VERSION 5.7 ;
  NOWIREEXTENSIONATPIN ON ;
  DIVIDERCHAR "/" ;
  BUSBITCHARS "[]" ;
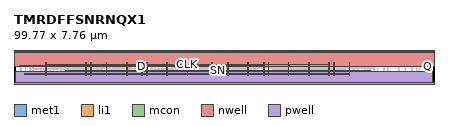
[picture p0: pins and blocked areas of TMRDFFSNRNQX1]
MACRO TMRDFFSNRNQX1
  CLASS CORE ;
  FOREIGN TMRDFFSNRNQX1 ;
  ORIGIN 0.000 0.000 ;
  SIZE 99.770 BY 7.760 ;
  SYMMETRY X Y ;
  SITE unitrh ;
  PIN Q
    DIRECTION OUTPUT ;
    USE SIGNAL ;
    ANTENNADIFFAREA 0.771900 ;
    PORT
      LAYER met1 ;
        RECT 98.425 4.335 98.655 4.365 ;
        RECT 98.395 4.165 98.805 4.335 ;
        RECT 98.425 4.135 98.655 4.165 ;
    END
  END Q
  PIN D
    DIRECTION INPUT ;
    USE SIGNAL ;
    ANTENNAGATEAREA 3.099750 ;
    PORT
      LAYER met1 ;
        RECT 1.485 4.335 1.715 4.365 ;
        RECT 30.345 4.335 30.575 4.365 ;
        RECT 59.205 4.335 59.435 4.365 ;
        RECT 1.335 4.165 59.465 4.335 ;
        RECT 1.485 4.135 1.715 4.165 ;
        RECT 30.345 4.135 30.575 4.165 ;
        RECT 59.205 4.135 59.435 4.165 ;
    END
    PORT
      LAYER li1 ;
        RECT 30.375 2.095 30.545 5.045 ;
      LAYER mcon ;
        RECT 30.375 4.165 30.545 4.335 ;
    END
    PORT
      LAYER li1 ;
        RECT 59.235 2.095 59.405 5.045 ;
      LAYER mcon ;
        RECT 59.235 4.165 59.405 4.335 ;
    END
  END D
  PIN CLK
    DIRECTION INPUT ;
    USE SIGNAL ;
    ANTENNAGATEAREA 6.089100 ;
    PORT
      LAYER met1 ;
        RECT 7.405 4.705 7.635 4.735 ;
        RECT 17.025 4.705 17.255 4.735 ;
        RECT 36.265 4.705 36.495 4.735 ;
        RECT 45.885 4.705 46.115 4.735 ;
        RECT 65.125 4.705 65.355 4.735 ;
        RECT 74.745 4.705 74.975 4.735 ;
        RECT 7.375 4.535 75.005 4.705 ;
        RECT 7.405 4.505 7.635 4.535 ;
        RECT 17.025 4.505 17.255 4.535 ;
        RECT 36.265 4.505 36.495 4.535 ;
        RECT 45.885 4.505 46.115 4.535 ;
        RECT 65.125 4.505 65.355 4.535 ;
        RECT 74.745 4.505 74.975 4.535 ;
    END
    PORT
      LAYER li1 ;
        RECT 36.295 2.095 36.465 5.045 ;
      LAYER mcon ;
        RECT 36.295 4.535 36.465 4.705 ;
    END
    PORT
      LAYER li1 ;
        RECT 17.055 2.095 17.225 5.045 ;
      LAYER mcon ;
        RECT 17.055 4.535 17.225 4.705 ;
    END
    PORT
      LAYER li1 ;
        RECT 7.435 2.095 7.605 5.045 ;
      LAYER mcon ;
        RECT 7.435 4.535 7.605 4.705 ;
    END
    PORT
      LAYER li1 ;
        RECT 65.155 2.095 65.325 5.045 ;
      LAYER mcon ;
        RECT 65.155 4.535 65.325 4.705 ;
    END
    PORT
      LAYER li1 ;
        RECT 74.775 2.095 74.945 5.045 ;
      LAYER mcon ;
        RECT 74.775 4.535 74.945 4.705 ;
    END
  END CLK
  PIN SN
    DIRECTION INPUT ;
    USE SIGNAL ;
    ANTENNAGATEAREA 6.089100 ;
    PORT
      LAYER met1 ;
        RECT 12.215 3.225 12.445 3.255 ;
        RECT 26.645 3.225 26.875 3.255 ;
        RECT 41.075 3.225 41.305 3.255 ;
        RECT 55.505 3.225 55.735 3.255 ;
        RECT 69.935 3.225 70.165 3.255 ;
        RECT 84.365 3.225 84.595 3.255 ;
        RECT 12.185 3.055 84.625 3.225 ;
        RECT 12.215 3.025 12.445 3.055 ;
        RECT 26.645 3.025 26.875 3.055 ;
        RECT 41.075 3.025 41.305 3.055 ;
        RECT 55.505 3.025 55.735 3.055 ;
        RECT 69.935 3.025 70.165 3.055 ;
        RECT 84.365 3.025 84.595 3.055 ;
    END
    PORT
      LAYER li1 ;
        RECT 26.675 2.095 26.845 5.045 ;
      LAYER mcon ;
        RECT 26.675 3.055 26.845 3.225 ;
    END
    PORT
      LAYER li1 ;
        RECT 41.105 2.095 41.275 5.045 ;
      LAYER mcon ;
        RECT 41.105 3.055 41.275 3.225 ;
    END
    PORT
      LAYER li1 ;
        RECT 55.535 2.095 55.705 5.045 ;
      LAYER mcon ;
        RECT 55.535 3.055 55.705 3.225 ;
    END
    PORT
      LAYER li1 ;
        RECT 69.965 2.095 70.135 5.045 ;
      LAYER mcon ;
        RECT 69.965 3.055 70.135 3.225 ;
    END
  END SN
  PIN RN
    DIRECTION INPUT ;
    USE SIGNAL ;
    ANTENNAGATEAREA 9.170850 ;
    PORT
      LAYER met1 ;
        RECT 2.595 2.485 2.825 2.515 ;
        RECT 18.135 2.485 18.365 2.515 ;
        RECT 21.835 2.485 22.065 2.515 ;
        RECT 31.455 2.485 31.685 2.515 ;
        RECT 46.995 2.485 47.225 2.515 ;
        RECT 50.695 2.485 50.925 2.515 ;
        RECT 60.315 2.485 60.545 2.515 ;
        RECT 75.855 2.485 76.085 2.515 ;
        RECT 79.555 2.485 79.785 2.515 ;
        RECT 2.565 2.315 79.815 2.485 ;
        RECT 2.595 2.285 2.825 2.315 ;
        RECT 18.135 2.285 18.365 2.315 ;
        RECT 21.835 2.285 22.065 2.315 ;
        RECT 31.455 2.285 31.685 2.315 ;
        RECT 46.995 2.285 47.225 2.315 ;
        RECT 50.695 2.285 50.925 2.315 ;
        RECT 60.315 2.285 60.545 2.315 ;
        RECT 75.855 2.285 76.085 2.315 ;
        RECT 79.555 2.285 79.785 2.315 ;
    END
    PORT
      LAYER li1 ;
        RECT 18.165 2.095 18.335 5.045 ;
      LAYER mcon ;
        RECT 18.165 2.315 18.335 2.485 ;
    END
    PORT
      LAYER li1 ;
        RECT 21.865 2.095 22.035 5.045 ;
      LAYER mcon ;
        RECT 21.865 2.315 22.035 2.485 ;
    END
    PORT
      LAYER li1 ;
        RECT 31.485 2.095 31.655 5.045 ;
      LAYER mcon ;
        RECT 31.485 2.315 31.655 2.485 ;
    END
    PORT
      LAYER li1 ;
        RECT 47.025 2.095 47.195 5.045 ;
      LAYER mcon ;
        RECT 47.025 2.315 47.195 2.485 ;
    END
    PORT
      LAYER li1 ;
        RECT 50.725 2.095 50.895 5.045 ;
      LAYER mcon ;
        RECT 50.725 2.315 50.895 2.485 ;
    END
    PORT
      LAYER li1 ;
        RECT 60.345 2.095 60.515 5.045 ;
      LAYER mcon ;
        RECT 60.345 2.315 60.515 2.485 ;
    END
    PORT
      LAYER li1 ;
        RECT 75.885 2.095 76.055 5.045 ;
      LAYER mcon ;
        RECT 75.885 2.315 76.055 2.485 ;
    END
    PORT
      LAYER li1 ;
        RECT 79.585 2.095 79.755 5.045 ;
      LAYER mcon ;
        RECT 79.585 2.315 79.755 2.485 ;
    END
  END RN
  PIN VDD
    DIRECTION INOUT ;
    USE POWER ;
    SHAPE ABUTMENT ;
    PORT
      LAYER nwell ;
        RECT 0.000 4.110 99.770 7.940 ;
      LAYER met1 ;
        RECT 0.000 7.410 99.770 7.760 ;
    END
  END VDD
  PIN GND
    DIRECTION INOUT ;
    USE GROUND ;
    SHAPE ABUTMENT ;
    PORT
      LAYER pwell ;
        RECT 0.320 0.000 99.450 2.900 ;
      LAYER met1 ;
        RECT 0.000 0.000 99.770 0.350 ;
    END
  END GND
  OBS
      LAYER li1 ;
        RECT 0.000 7.410 99.770 7.760 ;
        RECT 0.320 4.290 0.660 7.410 ;
        RECT 1.495 5.395 1.665 7.410 ;
        RECT 1.935 5.420 2.105 7.200 ;
        RECT 2.375 5.735 2.545 7.410 ;
        RECT 2.815 5.420 2.985 7.200 ;
        RECT 3.255 5.735 3.425 7.410 ;
        RECT 3.695 5.420 3.865 7.200 ;
        RECT 4.135 5.735 4.305 7.410 ;
        RECT 1.935 5.250 4.645 5.420 ;
        RECT 0.320 0.350 0.660 2.900 ;
        RECT 1.515 2.095 1.685 5.045 ;
        RECT 2.625 2.095 2.795 5.045 ;
        RECT 3.735 2.095 3.905 5.045 ;
        RECT 0.995 1.855 1.165 1.935 ;
        RECT 1.965 1.855 2.135 1.935 ;
        RECT 2.935 1.855 3.105 1.935 ;
        RECT 0.995 1.685 3.105 1.855 ;
        RECT 0.995 0.555 1.165 1.685 ;
        RECT 1.480 0.350 1.650 1.310 ;
        RECT 1.965 0.805 2.135 1.685 ;
        RECT 2.935 1.605 3.105 1.685 ;
        RECT 2.455 1.260 2.625 1.340 ;
        RECT 3.505 1.260 3.675 1.935 ;
        RECT 4.475 1.930 4.645 5.250 ;
        RECT 5.130 4.290 5.470 7.410 ;
        RECT 6.305 5.395 6.475 7.410 ;
        RECT 6.745 5.420 6.915 7.200 ;
        RECT 7.185 5.735 7.355 7.410 ;
        RECT 7.625 5.420 7.795 7.200 ;
        RECT 8.065 5.735 8.235 7.410 ;
        RECT 8.505 5.420 8.675 7.200 ;
        RECT 8.945 5.735 9.115 7.410 ;
        RECT 6.745 5.250 9.455 5.420 ;
        RECT 2.455 1.090 3.675 1.260 ;
        RECT 2.455 1.010 2.625 1.090 ;
        RECT 2.935 0.805 3.105 0.885 ;
        RECT 1.965 0.635 3.105 0.805 ;
        RECT 1.965 0.555 2.135 0.635 ;
        RECT 2.935 0.555 3.105 0.635 ;
        RECT 3.505 0.805 3.675 1.090 ;
        RECT 3.990 1.760 4.645 1.930 ;
        RECT 3.990 1.025 4.160 1.760 ;
        RECT 4.475 0.805 4.645 1.575 ;
        RECT 3.505 0.635 4.645 0.805 ;
        RECT 3.505 0.555 3.675 0.635 ;
        RECT 4.475 0.555 4.645 0.635 ;
        RECT 5.130 0.350 5.470 2.900 ;
        RECT 6.325 2.095 6.495 5.045 ;
        RECT 8.545 2.095 8.715 5.045 ;
        RECT 5.805 1.855 5.975 1.935 ;
        RECT 6.775 1.855 6.945 1.935 ;
        RECT 7.745 1.855 7.915 1.935 ;
        RECT 5.805 1.685 7.915 1.855 ;
        RECT 5.805 0.555 5.975 1.685 ;
        RECT 6.290 0.350 6.460 1.310 ;
        RECT 6.775 0.805 6.945 1.685 ;
        RECT 7.745 1.605 7.915 1.685 ;
        RECT 7.265 1.260 7.435 1.340 ;
        RECT 8.315 1.260 8.485 1.935 ;
        RECT 9.285 1.930 9.455 5.250 ;
        RECT 9.940 4.290 10.280 7.410 ;
        RECT 11.115 5.395 11.285 7.410 ;
        RECT 11.555 5.420 11.725 7.200 ;
        RECT 11.995 5.735 12.165 7.410 ;
        RECT 12.435 5.420 12.605 7.200 ;
        RECT 12.875 5.735 13.045 7.410 ;
        RECT 13.315 5.420 13.485 7.200 ;
        RECT 13.755 5.735 13.925 7.410 ;
        RECT 11.555 5.250 14.265 5.420 ;
        RECT 7.265 1.090 8.485 1.260 ;
        RECT 7.265 1.010 7.435 1.090 ;
        RECT 7.745 0.805 7.915 0.885 ;
        RECT 6.775 0.635 7.915 0.805 ;
        RECT 6.775 0.555 6.945 0.635 ;
        RECT 7.745 0.555 7.915 0.635 ;
        RECT 8.315 0.805 8.485 1.090 ;
        RECT 8.800 1.760 9.455 1.930 ;
        RECT 8.800 1.025 8.970 1.760 ;
        RECT 9.285 0.805 9.455 1.575 ;
        RECT 8.315 0.635 9.455 0.805 ;
        RECT 8.315 0.555 8.485 0.635 ;
        RECT 9.285 0.555 9.455 0.635 ;
        RECT 9.940 0.350 10.280 2.900 ;
        RECT 11.135 2.095 11.305 5.045 ;
        RECT 12.245 2.095 12.415 5.045 ;
        RECT 13.355 2.095 13.525 5.045 ;
        RECT 10.615 1.855 10.785 1.935 ;
        RECT 11.585 1.855 11.755 1.935 ;
        RECT 12.555 1.855 12.725 1.935 ;
        RECT 10.615 1.685 12.725 1.855 ;
        RECT 10.615 0.555 10.785 1.685 ;
        RECT 11.100 0.350 11.270 1.310 ;
        RECT 11.585 0.805 11.755 1.685 ;
        RECT 12.555 1.605 12.725 1.685 ;
        RECT 12.075 1.260 12.245 1.340 ;
        RECT 13.125 1.260 13.295 1.935 ;
        RECT 14.095 1.930 14.265 5.250 ;
        RECT 14.750 4.290 15.090 7.410 ;
        RECT 15.925 5.395 16.095 7.410 ;
        RECT 16.365 5.420 16.535 7.200 ;
        RECT 16.805 5.735 16.975 7.410 ;
        RECT 17.245 5.420 17.415 7.200 ;
        RECT 17.685 5.735 17.855 7.410 ;
        RECT 18.125 5.420 18.295 7.200 ;
        RECT 18.565 5.735 18.735 7.410 ;
        RECT 16.365 5.250 19.075 5.420 ;
        RECT 12.075 1.090 13.295 1.260 ;
        RECT 12.075 1.010 12.245 1.090 ;
        RECT 12.555 0.805 12.725 0.885 ;
        RECT 11.585 0.635 12.725 0.805 ;
        RECT 11.585 0.555 11.755 0.635 ;
        RECT 12.555 0.555 12.725 0.635 ;
        RECT 13.125 0.805 13.295 1.090 ;
        RECT 13.610 1.760 14.265 1.930 ;
        RECT 13.610 1.025 13.780 1.760 ;
        RECT 14.095 0.805 14.265 1.575 ;
        RECT 13.125 0.635 14.265 0.805 ;
        RECT 13.125 0.555 13.295 0.635 ;
        RECT 14.095 0.555 14.265 0.635 ;
        RECT 14.750 0.350 15.090 2.900 ;
        RECT 15.945 2.095 16.115 5.045 ;
        RECT 15.425 1.855 15.595 1.935 ;
        RECT 16.395 1.855 16.565 1.935 ;
        RECT 17.365 1.855 17.535 1.935 ;
        RECT 15.425 1.685 17.535 1.855 ;
        RECT 15.425 0.555 15.595 1.685 ;
        RECT 15.910 0.350 16.080 1.310 ;
        RECT 16.395 0.805 16.565 1.685 ;
        RECT 17.365 1.605 17.535 1.685 ;
        RECT 16.885 1.260 17.055 1.340 ;
        RECT 17.935 1.260 18.105 1.935 ;
        RECT 18.905 1.930 19.075 5.250 ;
        RECT 19.560 4.290 19.900 7.410 ;
        RECT 20.735 5.395 20.905 7.410 ;
        RECT 21.175 5.420 21.345 7.200 ;
        RECT 21.615 5.735 21.785 7.410 ;
        RECT 22.055 5.420 22.225 7.200 ;
        RECT 22.495 5.735 22.665 7.410 ;
        RECT 22.935 5.420 23.105 7.200 ;
        RECT 23.375 5.735 23.545 7.410 ;
        RECT 21.175 5.250 23.885 5.420 ;
        RECT 16.885 1.090 18.105 1.260 ;
        RECT 16.885 1.010 17.055 1.090 ;
        RECT 17.365 0.805 17.535 0.885 ;
        RECT 16.395 0.635 17.535 0.805 ;
        RECT 16.395 0.555 16.565 0.635 ;
        RECT 17.365 0.555 17.535 0.635 ;
        RECT 17.935 0.805 18.105 1.090 ;
        RECT 18.420 1.760 19.075 1.930 ;
        RECT 18.420 1.025 18.590 1.760 ;
        RECT 18.905 0.805 19.075 1.575 ;
        RECT 17.935 0.635 19.075 0.805 ;
        RECT 17.935 0.555 18.105 0.635 ;
        RECT 18.905 0.555 19.075 0.635 ;
        RECT 19.560 0.350 19.900 2.900 ;
        RECT 20.755 2.095 20.925 5.045 ;
        RECT 22.975 2.095 23.145 5.045 ;
        RECT 20.235 1.855 20.405 1.935 ;
        RECT 21.205 1.855 21.375 1.935 ;
        RECT 22.175 1.855 22.345 1.935 ;
        RECT 20.235 1.685 22.345 1.855 ;
        RECT 20.235 0.555 20.405 1.685 ;
        RECT 20.720 0.350 20.890 1.310 ;
        RECT 21.205 0.805 21.375 1.685 ;
        RECT 22.175 1.605 22.345 1.685 ;
        RECT 21.695 1.260 21.865 1.340 ;
        RECT 22.745 1.260 22.915 1.935 ;
        RECT 23.715 1.930 23.885 5.250 ;
        RECT 24.370 4.290 24.710 7.410 ;
        RECT 25.545 5.395 25.715 7.410 ;
        RECT 25.985 5.420 26.155 7.200 ;
        RECT 26.425 5.735 26.595 7.410 ;
        RECT 26.865 5.420 27.035 7.200 ;
        RECT 27.305 5.735 27.475 7.410 ;
        RECT 27.745 5.420 27.915 7.200 ;
        RECT 28.185 5.735 28.355 7.410 ;
        RECT 25.985 5.250 28.695 5.420 ;
        RECT 21.695 1.090 22.915 1.260 ;
        RECT 21.695 1.010 21.865 1.090 ;
        RECT 22.175 0.805 22.345 0.885 ;
        RECT 21.205 0.635 22.345 0.805 ;
        RECT 21.205 0.555 21.375 0.635 ;
        RECT 22.175 0.555 22.345 0.635 ;
        RECT 22.745 0.805 22.915 1.090 ;
        RECT 23.230 1.760 23.885 1.930 ;
        RECT 23.230 1.025 23.400 1.760 ;
        RECT 23.715 0.805 23.885 1.575 ;
        RECT 22.745 0.635 23.885 0.805 ;
        RECT 22.745 0.555 22.915 0.635 ;
        RECT 23.715 0.555 23.885 0.635 ;
        RECT 24.370 0.350 24.710 2.900 ;
        RECT 25.565 2.095 25.735 5.045 ;
        RECT 27.785 2.095 27.955 5.045 ;
        RECT 25.045 1.855 25.215 1.935 ;
        RECT 26.015 1.855 26.185 1.935 ;
        RECT 26.985 1.855 27.155 1.935 ;
        RECT 25.045 1.685 27.155 1.855 ;
        RECT 25.045 0.555 25.215 1.685 ;
        RECT 25.530 0.350 25.700 1.310 ;
        RECT 26.015 0.805 26.185 1.685 ;
        RECT 26.985 1.605 27.155 1.685 ;
        RECT 26.505 1.260 26.675 1.340 ;
        RECT 27.555 1.260 27.725 1.935 ;
        RECT 28.525 1.930 28.695 5.250 ;
        RECT 29.180 4.290 29.520 7.410 ;
        RECT 30.355 5.395 30.525 7.410 ;
        RECT 30.795 5.420 30.965 7.200 ;
        RECT 31.235 5.735 31.405 7.410 ;
        RECT 31.675 5.420 31.845 7.200 ;
        RECT 32.115 5.735 32.285 7.410 ;
        RECT 32.555 5.420 32.725 7.200 ;
        RECT 32.995 5.735 33.165 7.410 ;
        RECT 30.795 5.250 33.505 5.420 ;
        RECT 26.505 1.090 27.725 1.260 ;
        RECT 26.505 1.010 26.675 1.090 ;
        RECT 26.985 0.805 27.155 0.885 ;
        RECT 26.015 0.635 27.155 0.805 ;
        RECT 26.015 0.555 26.185 0.635 ;
        RECT 26.985 0.555 27.155 0.635 ;
        RECT 27.555 0.805 27.725 1.090 ;
        RECT 28.040 1.760 28.695 1.930 ;
        RECT 28.040 1.025 28.210 1.760 ;
        RECT 28.525 0.805 28.695 1.575 ;
        RECT 27.555 0.635 28.695 0.805 ;
        RECT 27.555 0.555 27.725 0.635 ;
        RECT 28.525 0.555 28.695 0.635 ;
        RECT 29.180 0.350 29.520 2.900 ;
        RECT 32.595 2.095 32.765 5.045 ;
        RECT 29.855 1.855 30.025 1.935 ;
        RECT 30.825 1.855 30.995 1.935 ;
        RECT 31.795 1.855 31.965 1.935 ;
        RECT 29.855 1.685 31.965 1.855 ;
        RECT 29.855 0.555 30.025 1.685 ;
        RECT 30.340 0.350 30.510 1.310 ;
        RECT 30.825 0.805 30.995 1.685 ;
        RECT 31.795 1.605 31.965 1.685 ;
        RECT 31.315 1.260 31.485 1.340 ;
        RECT 32.365 1.260 32.535 1.935 ;
        RECT 33.335 1.930 33.505 5.250 ;
        RECT 33.990 4.290 34.330 7.410 ;
        RECT 35.165 5.395 35.335 7.410 ;
        RECT 35.605 5.420 35.775 7.200 ;
        RECT 36.045 5.735 36.215 7.410 ;
        RECT 36.485 5.420 36.655 7.200 ;
        RECT 36.925 5.735 37.095 7.410 ;
        RECT 37.365 5.420 37.535 7.200 ;
        RECT 37.805 5.735 37.975 7.410 ;
        RECT 35.605 5.250 38.315 5.420 ;
        RECT 31.315 1.090 32.535 1.260 ;
        RECT 31.315 1.010 31.485 1.090 ;
        RECT 31.795 0.805 31.965 0.885 ;
        RECT 30.825 0.635 31.965 0.805 ;
        RECT 30.825 0.555 30.995 0.635 ;
        RECT 31.795 0.555 31.965 0.635 ;
        RECT 32.365 0.805 32.535 1.090 ;
        RECT 32.850 1.760 33.505 1.930 ;
        RECT 32.850 1.025 33.020 1.760 ;
        RECT 33.335 0.805 33.505 1.575 ;
        RECT 32.365 0.635 33.505 0.805 ;
        RECT 32.365 0.555 32.535 0.635 ;
        RECT 33.335 0.555 33.505 0.635 ;
        RECT 33.990 0.350 34.330 2.900 ;
        RECT 35.185 2.095 35.355 5.045 ;
        RECT 37.405 2.095 37.575 5.045 ;
        RECT 34.665 1.855 34.835 1.935 ;
        RECT 35.635 1.855 35.805 1.935 ;
        RECT 36.605 1.855 36.775 1.935 ;
        RECT 34.665 1.685 36.775 1.855 ;
        RECT 34.665 0.555 34.835 1.685 ;
        RECT 35.150 0.350 35.320 1.310 ;
        RECT 35.635 0.805 35.805 1.685 ;
        RECT 36.605 1.605 36.775 1.685 ;
        RECT 36.125 1.260 36.295 1.340 ;
        RECT 37.175 1.260 37.345 1.935 ;
        RECT 38.145 1.930 38.315 5.250 ;
        RECT 38.800 4.290 39.140 7.410 ;
        RECT 39.975 5.395 40.145 7.410 ;
        RECT 40.415 5.420 40.585 7.200 ;
        RECT 40.855 5.735 41.025 7.410 ;
        RECT 41.295 5.420 41.465 7.200 ;
        RECT 41.735 5.735 41.905 7.410 ;
        RECT 42.175 5.420 42.345 7.200 ;
        RECT 42.615 5.735 42.785 7.410 ;
        RECT 40.415 5.250 43.125 5.420 ;
        RECT 36.125 1.090 37.345 1.260 ;
        RECT 36.125 1.010 36.295 1.090 ;
        RECT 36.605 0.805 36.775 0.885 ;
        RECT 35.635 0.635 36.775 0.805 ;
        RECT 35.635 0.555 35.805 0.635 ;
        RECT 36.605 0.555 36.775 0.635 ;
        RECT 37.175 0.805 37.345 1.090 ;
        RECT 37.660 1.760 38.315 1.930 ;
        RECT 37.660 1.025 37.830 1.760 ;
        RECT 38.145 0.805 38.315 1.575 ;
        RECT 37.175 0.635 38.315 0.805 ;
        RECT 37.175 0.555 37.345 0.635 ;
        RECT 38.145 0.555 38.315 0.635 ;
        RECT 38.800 0.350 39.140 2.900 ;
        RECT 39.995 2.095 40.165 5.045 ;
        RECT 42.215 2.095 42.385 5.045 ;
        RECT 39.475 1.855 39.645 1.935 ;
        RECT 40.445 1.855 40.615 1.935 ;
        RECT 41.415 1.855 41.585 1.935 ;
        RECT 39.475 1.685 41.585 1.855 ;
        RECT 39.475 0.555 39.645 1.685 ;
        RECT 39.960 0.350 40.130 1.310 ;
        RECT 40.445 0.805 40.615 1.685 ;
        RECT 41.415 1.605 41.585 1.685 ;
        RECT 40.935 1.260 41.105 1.340 ;
        RECT 41.985 1.260 42.155 1.935 ;
        RECT 42.955 1.930 43.125 5.250 ;
        RECT 43.610 4.290 43.950 7.410 ;
        RECT 44.785 5.395 44.955 7.410 ;
        RECT 45.225 5.420 45.395 7.200 ;
        RECT 45.665 5.735 45.835 7.410 ;
        RECT 46.105 5.420 46.275 7.200 ;
        RECT 46.545 5.735 46.715 7.410 ;
        RECT 46.985 5.420 47.155 7.200 ;
        RECT 47.425 5.735 47.595 7.410 ;
        RECT 45.225 5.250 47.935 5.420 ;
        RECT 40.935 1.090 42.155 1.260 ;
        RECT 40.935 1.010 41.105 1.090 ;
        RECT 41.415 0.805 41.585 0.885 ;
        RECT 40.445 0.635 41.585 0.805 ;
        RECT 40.445 0.555 40.615 0.635 ;
        RECT 41.415 0.555 41.585 0.635 ;
        RECT 41.985 0.805 42.155 1.090 ;
        RECT 42.470 1.760 43.125 1.930 ;
        RECT 42.470 1.025 42.640 1.760 ;
        RECT 42.955 0.805 43.125 1.575 ;
        RECT 41.985 0.635 43.125 0.805 ;
        RECT 41.985 0.555 42.155 0.635 ;
        RECT 42.955 0.555 43.125 0.635 ;
        RECT 43.610 0.350 43.950 2.900 ;
        RECT 44.805 2.095 44.975 5.045 ;
        RECT 45.915 2.095 46.085 5.045 ;
        RECT 44.285 1.855 44.455 1.935 ;
        RECT 45.255 1.855 45.425 1.935 ;
        RECT 46.225 1.855 46.395 1.935 ;
        RECT 44.285 1.685 46.395 1.855 ;
        RECT 44.285 0.555 44.455 1.685 ;
        RECT 44.770 0.350 44.940 1.310 ;
        RECT 45.255 0.805 45.425 1.685 ;
        RECT 46.225 1.605 46.395 1.685 ;
        RECT 45.745 1.260 45.915 1.340 ;
        RECT 46.795 1.260 46.965 1.935 ;
        RECT 47.765 1.930 47.935 5.250 ;
        RECT 48.420 4.290 48.760 7.410 ;
        RECT 49.595 5.395 49.765 7.410 ;
        RECT 50.035 5.420 50.205 7.200 ;
        RECT 50.475 5.735 50.645 7.410 ;
        RECT 50.915 5.420 51.085 7.200 ;
        RECT 51.355 5.735 51.525 7.410 ;
        RECT 51.795 5.420 51.965 7.200 ;
        RECT 52.235 5.735 52.405 7.410 ;
        RECT 50.035 5.250 52.745 5.420 ;
        RECT 45.745 1.090 46.965 1.260 ;
        RECT 45.745 1.010 45.915 1.090 ;
        RECT 46.225 0.805 46.395 0.885 ;
        RECT 45.255 0.635 46.395 0.805 ;
        RECT 45.255 0.555 45.425 0.635 ;
        RECT 46.225 0.555 46.395 0.635 ;
        RECT 46.795 0.805 46.965 1.090 ;
        RECT 47.280 1.760 47.935 1.930 ;
        RECT 47.280 1.025 47.450 1.760 ;
        RECT 47.765 0.805 47.935 1.575 ;
        RECT 46.795 0.635 47.935 0.805 ;
        RECT 46.795 0.555 46.965 0.635 ;
        RECT 47.765 0.555 47.935 0.635 ;
        RECT 48.420 0.350 48.760 2.900 ;
        RECT 49.615 2.095 49.785 5.045 ;
        RECT 51.835 2.095 52.005 5.045 ;
        RECT 49.095 1.855 49.265 1.935 ;
        RECT 50.065 1.855 50.235 1.935 ;
        RECT 51.035 1.855 51.205 1.935 ;
        RECT 49.095 1.685 51.205 1.855 ;
        RECT 49.095 0.555 49.265 1.685 ;
        RECT 49.580 0.350 49.750 1.310 ;
        RECT 50.065 0.805 50.235 1.685 ;
        RECT 51.035 1.605 51.205 1.685 ;
        RECT 50.555 1.260 50.725 1.340 ;
        RECT 51.605 1.260 51.775 1.935 ;
        RECT 52.575 1.930 52.745 5.250 ;
        RECT 53.230 4.290 53.570 7.410 ;
        RECT 54.405 5.395 54.575 7.410 ;
        RECT 54.845 5.420 55.015 7.200 ;
        RECT 55.285 5.735 55.455 7.410 ;
        RECT 55.725 5.420 55.895 7.200 ;
        RECT 56.165 5.735 56.335 7.410 ;
        RECT 56.605 5.420 56.775 7.200 ;
        RECT 57.045 5.735 57.215 7.410 ;
        RECT 54.845 5.250 57.555 5.420 ;
        RECT 50.555 1.090 51.775 1.260 ;
        RECT 50.555 1.010 50.725 1.090 ;
        RECT 51.035 0.805 51.205 0.885 ;
        RECT 50.065 0.635 51.205 0.805 ;
        RECT 50.065 0.555 50.235 0.635 ;
        RECT 51.035 0.555 51.205 0.635 ;
        RECT 51.605 0.805 51.775 1.090 ;
        RECT 52.090 1.760 52.745 1.930 ;
        RECT 52.090 1.025 52.260 1.760 ;
        RECT 52.575 0.805 52.745 1.575 ;
        RECT 51.605 0.635 52.745 0.805 ;
        RECT 51.605 0.555 51.775 0.635 ;
        RECT 52.575 0.555 52.745 0.635 ;
        RECT 53.230 0.350 53.570 2.900 ;
        RECT 54.425 2.095 54.595 5.045 ;
        RECT 56.645 2.095 56.815 5.045 ;
        RECT 53.905 1.855 54.075 1.935 ;
        RECT 54.875 1.855 55.045 1.935 ;
        RECT 55.845 1.855 56.015 1.935 ;
        RECT 53.905 1.685 56.015 1.855 ;
        RECT 53.905 0.555 54.075 1.685 ;
        RECT 54.390 0.350 54.560 1.310 ;
        RECT 54.875 0.805 55.045 1.685 ;
        RECT 55.845 1.605 56.015 1.685 ;
        RECT 55.365 1.260 55.535 1.340 ;
        RECT 56.415 1.260 56.585 1.935 ;
        RECT 57.385 1.930 57.555 5.250 ;
        RECT 58.040 4.290 58.380 7.410 ;
        RECT 59.215 5.395 59.385 7.410 ;
        RECT 59.655 5.420 59.825 7.200 ;
        RECT 60.095 5.735 60.265 7.410 ;
        RECT 60.535 5.420 60.705 7.200 ;
        RECT 60.975 5.735 61.145 7.410 ;
        RECT 61.415 5.420 61.585 7.200 ;
        RECT 61.855 5.735 62.025 7.410 ;
        RECT 59.655 5.250 62.365 5.420 ;
        RECT 55.365 1.090 56.585 1.260 ;
        RECT 55.365 1.010 55.535 1.090 ;
        RECT 55.845 0.805 56.015 0.885 ;
        RECT 54.875 0.635 56.015 0.805 ;
        RECT 54.875 0.555 55.045 0.635 ;
        RECT 55.845 0.555 56.015 0.635 ;
        RECT 56.415 0.805 56.585 1.090 ;
        RECT 56.900 1.760 57.555 1.930 ;
        RECT 56.900 1.025 57.070 1.760 ;
        RECT 57.385 0.805 57.555 1.575 ;
        RECT 56.415 0.635 57.555 0.805 ;
        RECT 56.415 0.555 56.585 0.635 ;
        RECT 57.385 0.555 57.555 0.635 ;
        RECT 58.040 0.350 58.380 2.900 ;
        RECT 61.455 2.095 61.625 5.045 ;
        RECT 58.715 1.855 58.885 1.935 ;
        RECT 59.685 1.855 59.855 1.935 ;
        RECT 60.655 1.855 60.825 1.935 ;
        RECT 58.715 1.685 60.825 1.855 ;
        RECT 58.715 0.555 58.885 1.685 ;
        RECT 59.200 0.350 59.370 1.310 ;
        RECT 59.685 0.805 59.855 1.685 ;
        RECT 60.655 1.605 60.825 1.685 ;
        RECT 60.175 1.260 60.345 1.340 ;
        RECT 61.225 1.260 61.395 1.935 ;
        RECT 62.195 1.930 62.365 5.250 ;
        RECT 62.850 4.290 63.190 7.410 ;
        RECT 64.025 5.395 64.195 7.410 ;
        RECT 64.465 5.420 64.635 7.200 ;
        RECT 64.905 5.735 65.075 7.410 ;
        RECT 65.345 5.420 65.515 7.200 ;
        RECT 65.785 5.735 65.955 7.410 ;
        RECT 66.225 5.420 66.395 7.200 ;
        RECT 66.665 5.735 66.835 7.410 ;
        RECT 64.465 5.250 67.175 5.420 ;
        RECT 60.175 1.090 61.395 1.260 ;
        RECT 60.175 1.010 60.345 1.090 ;
        RECT 60.655 0.805 60.825 0.885 ;
        RECT 59.685 0.635 60.825 0.805 ;
        RECT 59.685 0.555 59.855 0.635 ;
        RECT 60.655 0.555 60.825 0.635 ;
        RECT 61.225 0.805 61.395 1.090 ;
        RECT 61.710 1.760 62.365 1.930 ;
        RECT 61.710 1.025 61.880 1.760 ;
        RECT 62.195 0.805 62.365 1.575 ;
        RECT 61.225 0.635 62.365 0.805 ;
        RECT 61.225 0.555 61.395 0.635 ;
        RECT 62.195 0.555 62.365 0.635 ;
        RECT 62.850 0.350 63.190 2.900 ;
        RECT 64.045 2.095 64.215 5.045 ;
        RECT 66.265 2.095 66.435 5.045 ;
        RECT 63.525 1.855 63.695 1.935 ;
        RECT 64.495 1.855 64.665 1.935 ;
        RECT 65.465 1.855 65.635 1.935 ;
        RECT 63.525 1.685 65.635 1.855 ;
        RECT 63.525 0.555 63.695 1.685 ;
        RECT 64.010 0.350 64.180 1.310 ;
        RECT 64.495 0.805 64.665 1.685 ;
        RECT 65.465 1.605 65.635 1.685 ;
        RECT 64.985 1.260 65.155 1.340 ;
        RECT 66.035 1.260 66.205 1.935 ;
        RECT 67.005 1.930 67.175 5.250 ;
        RECT 67.660 4.290 68.000 7.410 ;
        RECT 68.835 5.395 69.005 7.410 ;
        RECT 69.275 5.420 69.445 7.200 ;
        RECT 69.715 5.735 69.885 7.410 ;
        RECT 70.155 5.420 70.325 7.200 ;
        RECT 70.595 5.735 70.765 7.410 ;
        RECT 71.035 5.420 71.205 7.200 ;
        RECT 71.475 5.735 71.645 7.410 ;
        RECT 69.275 5.250 71.985 5.420 ;
        RECT 64.985 1.090 66.205 1.260 ;
        RECT 64.985 1.010 65.155 1.090 ;
        RECT 65.465 0.805 65.635 0.885 ;
        RECT 64.495 0.635 65.635 0.805 ;
        RECT 64.495 0.555 64.665 0.635 ;
        RECT 65.465 0.555 65.635 0.635 ;
        RECT 66.035 0.805 66.205 1.090 ;
        RECT 66.520 1.760 67.175 1.930 ;
        RECT 66.520 1.025 66.690 1.760 ;
        RECT 67.005 0.805 67.175 1.575 ;
        RECT 66.035 0.635 67.175 0.805 ;
        RECT 66.035 0.555 66.205 0.635 ;
        RECT 67.005 0.555 67.175 0.635 ;
        RECT 67.660 0.350 68.000 2.900 ;
        RECT 68.855 2.095 69.025 5.045 ;
        RECT 71.075 2.095 71.245 5.045 ;
        RECT 68.335 1.855 68.505 1.935 ;
        RECT 69.305 1.855 69.475 1.935 ;
        RECT 70.275 1.855 70.445 1.935 ;
        RECT 68.335 1.685 70.445 1.855 ;
        RECT 68.335 0.555 68.505 1.685 ;
        RECT 68.820 0.350 68.990 1.310 ;
        RECT 69.305 0.805 69.475 1.685 ;
        RECT 70.275 1.605 70.445 1.685 ;
        RECT 69.795 1.260 69.965 1.340 ;
        RECT 70.845 1.260 71.015 1.935 ;
        RECT 71.815 1.930 71.985 5.250 ;
        RECT 72.470 4.290 72.810 7.410 ;
        RECT 73.645 5.395 73.815 7.410 ;
        RECT 74.085 5.420 74.255 7.200 ;
        RECT 74.525 5.735 74.695 7.410 ;
        RECT 74.965 5.420 75.135 7.200 ;
        RECT 75.405 5.735 75.575 7.410 ;
        RECT 75.845 5.420 76.015 7.200 ;
        RECT 76.285 5.735 76.455 7.410 ;
        RECT 74.085 5.250 76.795 5.420 ;
        RECT 69.795 1.090 71.015 1.260 ;
        RECT 69.795 1.010 69.965 1.090 ;
        RECT 70.275 0.805 70.445 0.885 ;
        RECT 69.305 0.635 70.445 0.805 ;
        RECT 69.305 0.555 69.475 0.635 ;
        RECT 70.275 0.555 70.445 0.635 ;
        RECT 70.845 0.805 71.015 1.090 ;
        RECT 71.330 1.760 71.985 1.930 ;
        RECT 71.330 1.025 71.500 1.760 ;
        RECT 71.815 0.805 71.985 1.575 ;
        RECT 70.845 0.635 71.985 0.805 ;
        RECT 70.845 0.555 71.015 0.635 ;
        RECT 71.815 0.555 71.985 0.635 ;
        RECT 72.470 0.350 72.810 2.900 ;
        RECT 73.665 2.095 73.835 5.045 ;
        RECT 73.145 1.855 73.315 1.935 ;
        RECT 74.115 1.855 74.285 1.935 ;
        RECT 75.085 1.855 75.255 1.935 ;
        RECT 73.145 1.685 75.255 1.855 ;
        RECT 73.145 0.555 73.315 1.685 ;
        RECT 73.630 0.350 73.800 1.310 ;
        RECT 74.115 0.805 74.285 1.685 ;
        RECT 75.085 1.605 75.255 1.685 ;
        RECT 74.605 1.260 74.775 1.340 ;
        RECT 75.655 1.260 75.825 1.935 ;
        RECT 76.625 1.930 76.795 5.250 ;
        RECT 77.280 4.290 77.620 7.410 ;
        RECT 78.455 5.395 78.625 7.410 ;
        RECT 78.895 5.420 79.065 7.200 ;
        RECT 79.335 5.735 79.505 7.410 ;
        RECT 79.775 5.420 79.945 7.200 ;
        RECT 80.215 5.735 80.385 7.410 ;
        RECT 80.655 5.420 80.825 7.200 ;
        RECT 81.095 5.735 81.265 7.410 ;
        RECT 78.895 5.250 81.605 5.420 ;
        RECT 74.605 1.090 75.825 1.260 ;
        RECT 74.605 1.010 74.775 1.090 ;
        RECT 75.085 0.805 75.255 0.885 ;
        RECT 74.115 0.635 75.255 0.805 ;
        RECT 74.115 0.555 74.285 0.635 ;
        RECT 75.085 0.555 75.255 0.635 ;
        RECT 75.655 0.805 75.825 1.090 ;
        RECT 76.140 1.760 76.795 1.930 ;
        RECT 76.140 1.025 76.310 1.760 ;
        RECT 76.625 0.805 76.795 1.575 ;
        RECT 75.655 0.635 76.795 0.805 ;
        RECT 75.655 0.555 75.825 0.635 ;
        RECT 76.625 0.555 76.795 0.635 ;
        RECT 77.280 0.350 77.620 2.900 ;
        RECT 78.475 2.095 78.645 5.045 ;
        RECT 80.695 2.095 80.865 5.045 ;
        RECT 77.955 1.855 78.125 1.935 ;
        RECT 78.925 1.855 79.095 1.935 ;
        RECT 79.895 1.855 80.065 1.935 ;
        RECT 77.955 1.685 80.065 1.855 ;
        RECT 77.955 0.555 78.125 1.685 ;
        RECT 78.440 0.350 78.610 1.310 ;
        RECT 78.925 0.805 79.095 1.685 ;
        RECT 79.895 1.605 80.065 1.685 ;
        RECT 79.415 1.260 79.585 1.340 ;
        RECT 80.465 1.260 80.635 1.935 ;
        RECT 81.435 1.930 81.605 5.250 ;
        RECT 82.090 4.290 82.430 7.410 ;
        RECT 83.265 5.395 83.435 7.410 ;
        RECT 83.705 5.420 83.875 7.200 ;
        RECT 84.145 5.735 84.315 7.410 ;
        RECT 84.585 5.420 84.755 7.200 ;
        RECT 85.025 5.735 85.195 7.410 ;
        RECT 85.465 5.420 85.635 7.200 ;
        RECT 85.905 5.735 86.075 7.410 ;
        RECT 83.705 5.250 86.415 5.420 ;
        RECT 79.415 1.090 80.635 1.260 ;
        RECT 79.415 1.010 79.585 1.090 ;
        RECT 79.895 0.805 80.065 0.885 ;
        RECT 78.925 0.635 80.065 0.805 ;
        RECT 78.925 0.555 79.095 0.635 ;
        RECT 79.895 0.555 80.065 0.635 ;
        RECT 80.465 0.805 80.635 1.090 ;
        RECT 80.950 1.760 81.605 1.930 ;
        RECT 80.950 1.025 81.120 1.760 ;
        RECT 81.435 0.805 81.605 1.575 ;
        RECT 80.465 0.635 81.605 0.805 ;
        RECT 80.465 0.555 80.635 0.635 ;
        RECT 81.435 0.555 81.605 0.635 ;
        RECT 82.090 0.350 82.430 2.900 ;
        RECT 83.285 2.095 83.455 5.045 ;
        RECT 84.395 2.095 84.565 5.045 ;
        RECT 85.505 2.095 85.675 5.045 ;
        RECT 82.765 1.855 82.935 1.935 ;
        RECT 83.735 1.855 83.905 1.935 ;
        RECT 84.705 1.855 84.875 1.935 ;
        RECT 82.765 1.685 84.875 1.855 ;
        RECT 82.765 0.555 82.935 1.685 ;
        RECT 83.250 0.350 83.420 1.310 ;
        RECT 83.735 0.805 83.905 1.685 ;
        RECT 84.705 1.605 84.875 1.685 ;
        RECT 84.225 1.260 84.395 1.340 ;
        RECT 85.275 1.260 85.445 1.935 ;
        RECT 86.245 1.930 86.415 5.250 ;
        RECT 86.900 4.290 87.240 7.410 ;
        RECT 87.775 5.305 87.945 7.410 ;
        RECT 88.215 7.005 88.395 7.175 ;
        RECT 88.215 5.475 88.385 7.005 ;
        RECT 88.655 5.735 88.825 7.410 ;
        RECT 89.095 5.475 89.265 7.175 ;
        RECT 88.215 5.305 89.265 5.475 ;
        RECT 89.535 5.305 89.705 7.410 ;
        RECT 89.095 5.225 89.265 5.305 ;
        RECT 84.225 1.090 85.445 1.260 ;
        RECT 84.225 1.010 84.395 1.090 ;
        RECT 84.705 0.805 84.875 0.885 ;
        RECT 83.735 0.635 84.875 0.805 ;
        RECT 83.735 0.555 83.905 0.635 ;
        RECT 84.705 0.555 84.875 0.635 ;
        RECT 85.275 0.805 85.445 1.090 ;
        RECT 85.760 1.760 86.415 1.930 ;
        RECT 85.760 1.025 85.930 1.760 ;
        RECT 86.245 0.805 86.415 1.575 ;
        RECT 85.275 0.635 86.415 0.805 ;
        RECT 85.275 0.555 85.445 0.635 ;
        RECT 86.245 0.555 86.415 0.635 ;
        RECT 86.900 0.350 87.240 2.900 ;
        RECT 87.725 2.095 87.895 5.050 ;
        RECT 88.875 4.890 89.045 5.050 ;
        RECT 88.835 4.720 89.045 4.890 ;
        RECT 88.835 2.095 89.005 4.720 ;
        RECT 90.230 4.290 90.570 7.410 ;
        RECT 91.095 7.005 93.025 7.175 ;
        RECT 91.095 5.225 91.265 7.005 ;
        RECT 91.535 5.475 91.705 6.745 ;
        RECT 91.975 5.735 92.145 7.005 ;
        RECT 92.415 5.475 92.585 6.745 ;
        RECT 92.855 5.555 93.025 7.005 ;
        RECT 91.535 5.305 92.585 5.475 ;
        RECT 92.415 5.225 92.585 5.305 ;
        RECT 87.680 1.845 87.850 1.925 ;
        RECT 88.650 1.845 88.820 1.925 ;
        RECT 87.680 1.675 88.820 1.845 ;
        RECT 87.680 0.545 87.850 1.675 ;
        RECT 88.165 0.350 88.335 1.300 ;
        RECT 88.650 0.795 88.820 1.675 ;
        RECT 89.135 1.350 89.305 1.525 ;
        RECT 89.130 1.195 89.305 1.350 ;
        RECT 89.130 1.015 89.300 1.195 ;
        RECT 89.620 0.795 89.790 1.925 ;
        RECT 88.650 0.625 89.790 0.795 ;
        RECT 88.650 0.545 88.820 0.625 ;
        RECT 89.620 0.545 89.790 0.625 ;
        RECT 90.230 0.350 90.570 2.900 ;
        RECT 91.425 2.095 91.595 5.050 ;
        RECT 92.905 2.095 93.075 5.050 ;
        RECT 93.560 4.290 93.900 7.410 ;
        RECT 94.435 7.005 96.365 7.175 ;
        RECT 94.435 5.225 94.605 7.005 ;
        RECT 94.875 5.475 95.045 6.745 ;
        RECT 95.315 5.735 95.485 7.005 ;
        RECT 95.755 5.475 95.925 6.745 ;
        RECT 96.195 5.735 96.365 7.005 ;
        RECT 94.875 5.305 96.405 5.475 ;
        RECT 91.010 1.845 91.180 1.925 ;
        RECT 91.980 1.845 92.150 1.925 ;
        RECT 91.010 1.675 92.150 1.845 ;
        RECT 91.010 0.545 91.180 1.675 ;
        RECT 91.495 0.350 91.665 1.300 ;
        RECT 91.980 0.795 92.150 1.675 ;
        RECT 92.465 1.015 92.635 1.525 ;
        RECT 92.950 0.795 93.120 1.925 ;
        RECT 91.980 0.625 93.120 0.795 ;
        RECT 91.980 0.545 92.150 0.625 ;
        RECT 92.950 0.545 93.120 0.625 ;
        RECT 93.560 0.350 93.900 2.900 ;
        RECT 94.385 2.095 94.555 5.050 ;
        RECT 95.495 4.720 95.685 5.050 ;
        RECT 95.495 2.095 95.665 4.720 ;
        RECT 94.340 1.845 94.510 1.925 ;
        RECT 95.310 1.845 95.480 1.925 ;
        RECT 96.235 1.910 96.405 5.305 ;
        RECT 96.890 4.290 97.230 7.410 ;
        RECT 97.650 5.365 97.820 7.410 ;
        RECT 94.340 1.675 95.480 1.845 ;
        RECT 94.340 0.545 94.510 1.675 ;
        RECT 94.825 0.350 94.995 1.300 ;
        RECT 95.310 0.795 95.480 1.675 ;
        RECT 95.795 1.740 96.405 1.910 ;
        RECT 95.795 1.015 95.965 1.740 ;
        RECT 96.280 0.795 96.450 1.570 ;
        RECT 95.310 0.625 96.450 0.795 ;
        RECT 95.310 0.545 95.480 0.625 ;
        RECT 96.280 0.545 96.450 0.625 ;
        RECT 96.890 0.350 97.230 2.900 ;
        RECT 97.715 2.100 97.885 5.045 ;
        RECT 98.090 4.845 98.260 7.200 ;
        RECT 98.530 5.365 98.700 7.410 ;
        RECT 98.090 4.675 98.625 4.845 ;
        RECT 98.455 2.345 98.625 4.675 ;
        RECT 99.110 4.290 99.450 7.410 ;
        RECT 98.085 2.175 98.625 2.345 ;
        RECT 97.605 0.800 97.775 1.930 ;
        RECT 98.085 1.020 98.255 2.175 ;
        RECT 98.575 0.800 98.745 1.930 ;
        RECT 97.605 0.630 98.745 0.800 ;
        RECT 97.605 0.350 97.775 0.630 ;
        RECT 98.090 0.350 98.260 0.630 ;
        RECT 98.575 0.350 98.745 0.630 ;
        RECT 99.110 0.350 99.450 2.900 ;
        RECT 0.000 0.000 99.770 0.350 ;
      LAYER mcon ;
        RECT 0.775 7.495 0.945 7.665 ;
        RECT 1.145 7.495 1.315 7.665 ;
        RECT 1.515 7.495 1.685 7.665 ;
        RECT 1.885 7.495 2.055 7.665 ;
        RECT 2.255 7.495 2.425 7.665 ;
        RECT 2.625 7.495 2.795 7.665 ;
        RECT 2.995 7.495 3.165 7.665 ;
        RECT 3.365 7.495 3.535 7.665 ;
        RECT 3.735 7.495 3.905 7.665 ;
        RECT 4.105 7.495 4.275 7.665 ;
        RECT 4.475 7.495 4.645 7.665 ;
        RECT 4.845 7.495 5.015 7.665 ;
        RECT 5.585 7.495 5.755 7.665 ;
        RECT 5.955 7.495 6.125 7.665 ;
        RECT 6.325 7.495 6.495 7.665 ;
        RECT 6.695 7.495 6.865 7.665 ;
        RECT 7.065 7.495 7.235 7.665 ;
        RECT 7.435 7.495 7.605 7.665 ;
        RECT 7.805 7.495 7.975 7.665 ;
        RECT 8.175 7.495 8.345 7.665 ;
        RECT 8.545 7.495 8.715 7.665 ;
        RECT 8.915 7.495 9.085 7.665 ;
        RECT 9.285 7.495 9.455 7.665 ;
        RECT 9.655 7.495 9.825 7.665 ;
        RECT 10.395 7.495 10.565 7.665 ;
        RECT 10.765 7.495 10.935 7.665 ;
        RECT 11.135 7.495 11.305 7.665 ;
        RECT 11.505 7.495 11.675 7.665 ;
        RECT 11.875 7.495 12.045 7.665 ;
        RECT 12.245 7.495 12.415 7.665 ;
        RECT 12.615 7.495 12.785 7.665 ;
        RECT 12.985 7.495 13.155 7.665 ;
        RECT 13.355 7.495 13.525 7.665 ;
        RECT 13.725 7.495 13.895 7.665 ;
        RECT 14.095 7.495 14.265 7.665 ;
        RECT 14.465 7.495 14.635 7.665 ;
        RECT 15.205 7.495 15.375 7.665 ;
        RECT 15.575 7.495 15.745 7.665 ;
        RECT 15.945 7.495 16.115 7.665 ;
        RECT 16.315 7.495 16.485 7.665 ;
        RECT 16.685 7.495 16.855 7.665 ;
        RECT 17.055 7.495 17.225 7.665 ;
        RECT 17.425 7.495 17.595 7.665 ;
        RECT 17.795 7.495 17.965 7.665 ;
        RECT 18.165 7.495 18.335 7.665 ;
        RECT 18.535 7.495 18.705 7.665 ;
        RECT 18.905 7.495 19.075 7.665 ;
        RECT 19.275 7.495 19.445 7.665 ;
        RECT 20.015 7.495 20.185 7.665 ;
        RECT 20.385 7.495 20.555 7.665 ;
        RECT 20.755 7.495 20.925 7.665 ;
        RECT 21.125 7.495 21.295 7.665 ;
        RECT 21.495 7.495 21.665 7.665 ;
        RECT 21.865 7.495 22.035 7.665 ;
        RECT 22.235 7.495 22.405 7.665 ;
        RECT 22.605 7.495 22.775 7.665 ;
        RECT 22.975 7.495 23.145 7.665 ;
        RECT 23.345 7.495 23.515 7.665 ;
        RECT 23.715 7.495 23.885 7.665 ;
        RECT 24.085 7.495 24.255 7.665 ;
        RECT 24.825 7.495 24.995 7.665 ;
        RECT 25.195 7.495 25.365 7.665 ;
        RECT 25.565 7.495 25.735 7.665 ;
        RECT 25.935 7.495 26.105 7.665 ;
        RECT 26.305 7.495 26.475 7.665 ;
        RECT 26.675 7.495 26.845 7.665 ;
        RECT 27.045 7.495 27.215 7.665 ;
        RECT 27.415 7.495 27.585 7.665 ;
        RECT 27.785 7.495 27.955 7.665 ;
        RECT 28.155 7.495 28.325 7.665 ;
        RECT 28.525 7.495 28.695 7.665 ;
        RECT 28.895 7.495 29.065 7.665 ;
        RECT 29.635 7.495 29.805 7.665 ;
        RECT 30.005 7.495 30.175 7.665 ;
        RECT 30.375 7.495 30.545 7.665 ;
        RECT 30.745 7.495 30.915 7.665 ;
        RECT 31.115 7.495 31.285 7.665 ;
        RECT 31.485 7.495 31.655 7.665 ;
        RECT 31.855 7.495 32.025 7.665 ;
        RECT 32.225 7.495 32.395 7.665 ;
        RECT 32.595 7.495 32.765 7.665 ;
        RECT 32.965 7.495 33.135 7.665 ;
        RECT 33.335 7.495 33.505 7.665 ;
        RECT 33.705 7.495 33.875 7.665 ;
        RECT 34.445 7.495 34.615 7.665 ;
        RECT 34.815 7.495 34.985 7.665 ;
        RECT 35.185 7.495 35.355 7.665 ;
        RECT 35.555 7.495 35.725 7.665 ;
        RECT 35.925 7.495 36.095 7.665 ;
        RECT 36.295 7.495 36.465 7.665 ;
        RECT 36.665 7.495 36.835 7.665 ;
        RECT 37.035 7.495 37.205 7.665 ;
        RECT 37.405 7.495 37.575 7.665 ;
        RECT 37.775 7.495 37.945 7.665 ;
        RECT 38.145 7.495 38.315 7.665 ;
        RECT 38.515 7.495 38.685 7.665 ;
        RECT 39.255 7.495 39.425 7.665 ;
        RECT 39.625 7.495 39.795 7.665 ;
        RECT 39.995 7.495 40.165 7.665 ;
        RECT 40.365 7.495 40.535 7.665 ;
        RECT 40.735 7.495 40.905 7.665 ;
        RECT 41.105 7.495 41.275 7.665 ;
        RECT 41.475 7.495 41.645 7.665 ;
        RECT 41.845 7.495 42.015 7.665 ;
        RECT 42.215 7.495 42.385 7.665 ;
        RECT 42.585 7.495 42.755 7.665 ;
        RECT 42.955 7.495 43.125 7.665 ;
        RECT 43.325 7.495 43.495 7.665 ;
        RECT 44.065 7.495 44.235 7.665 ;
        RECT 44.435 7.495 44.605 7.665 ;
        RECT 44.805 7.495 44.975 7.665 ;
        RECT 45.175 7.495 45.345 7.665 ;
        RECT 45.545 7.495 45.715 7.665 ;
        RECT 45.915 7.495 46.085 7.665 ;
        RECT 46.285 7.495 46.455 7.665 ;
        RECT 46.655 7.495 46.825 7.665 ;
        RECT 47.025 7.495 47.195 7.665 ;
        RECT 47.395 7.495 47.565 7.665 ;
        RECT 47.765 7.495 47.935 7.665 ;
        RECT 48.135 7.495 48.305 7.665 ;
        RECT 48.875 7.495 49.045 7.665 ;
        RECT 49.245 7.495 49.415 7.665 ;
        RECT 49.615 7.495 49.785 7.665 ;
        RECT 49.985 7.495 50.155 7.665 ;
        RECT 50.355 7.495 50.525 7.665 ;
        RECT 50.725 7.495 50.895 7.665 ;
        RECT 51.095 7.495 51.265 7.665 ;
        RECT 51.465 7.495 51.635 7.665 ;
        RECT 51.835 7.495 52.005 7.665 ;
        RECT 52.205 7.495 52.375 7.665 ;
        RECT 52.575 7.495 52.745 7.665 ;
        RECT 52.945 7.495 53.115 7.665 ;
        RECT 53.685 7.495 53.855 7.665 ;
        RECT 54.055 7.495 54.225 7.665 ;
        RECT 54.425 7.495 54.595 7.665 ;
        RECT 54.795 7.495 54.965 7.665 ;
        RECT 55.165 7.495 55.335 7.665 ;
        RECT 55.535 7.495 55.705 7.665 ;
        RECT 55.905 7.495 56.075 7.665 ;
        RECT 56.275 7.495 56.445 7.665 ;
        RECT 56.645 7.495 56.815 7.665 ;
        RECT 57.015 7.495 57.185 7.665 ;
        RECT 57.385 7.495 57.555 7.665 ;
        RECT 57.755 7.495 57.925 7.665 ;
        RECT 58.495 7.495 58.665 7.665 ;
        RECT 58.865 7.495 59.035 7.665 ;
        RECT 59.235 7.495 59.405 7.665 ;
        RECT 59.605 7.495 59.775 7.665 ;
        RECT 59.975 7.495 60.145 7.665 ;
        RECT 60.345 7.495 60.515 7.665 ;
        RECT 60.715 7.495 60.885 7.665 ;
        RECT 61.085 7.495 61.255 7.665 ;
        RECT 61.455 7.495 61.625 7.665 ;
        RECT 61.825 7.495 61.995 7.665 ;
        RECT 62.195 7.495 62.365 7.665 ;
        RECT 62.565 7.495 62.735 7.665 ;
        RECT 63.305 7.495 63.475 7.665 ;
        RECT 63.675 7.495 63.845 7.665 ;
        RECT 64.045 7.495 64.215 7.665 ;
        RECT 64.415 7.495 64.585 7.665 ;
        RECT 64.785 7.495 64.955 7.665 ;
        RECT 65.155 7.495 65.325 7.665 ;
        RECT 65.525 7.495 65.695 7.665 ;
        RECT 65.895 7.495 66.065 7.665 ;
        RECT 66.265 7.495 66.435 7.665 ;
        RECT 66.635 7.495 66.805 7.665 ;
        RECT 67.005 7.495 67.175 7.665 ;
        RECT 67.375 7.495 67.545 7.665 ;
        RECT 68.115 7.495 68.285 7.665 ;
        RECT 68.485 7.495 68.655 7.665 ;
        RECT 68.855 7.495 69.025 7.665 ;
        RECT 69.225 7.495 69.395 7.665 ;
        RECT 69.595 7.495 69.765 7.665 ;
        RECT 69.965 7.495 70.135 7.665 ;
        RECT 70.335 7.495 70.505 7.665 ;
        RECT 70.705 7.495 70.875 7.665 ;
        RECT 71.075 7.495 71.245 7.665 ;
        RECT 71.445 7.495 71.615 7.665 ;
        RECT 71.815 7.495 71.985 7.665 ;
        RECT 72.185 7.495 72.355 7.665 ;
        RECT 72.925 7.495 73.095 7.665 ;
        RECT 73.295 7.495 73.465 7.665 ;
        RECT 73.665 7.495 73.835 7.665 ;
        RECT 74.035 7.495 74.205 7.665 ;
        RECT 74.405 7.495 74.575 7.665 ;
        RECT 74.775 7.495 74.945 7.665 ;
        RECT 75.145 7.495 75.315 7.665 ;
        RECT 75.515 7.495 75.685 7.665 ;
        RECT 75.885 7.495 76.055 7.665 ;
        RECT 76.255 7.495 76.425 7.665 ;
        RECT 76.625 7.495 76.795 7.665 ;
        RECT 76.995 7.495 77.165 7.665 ;
        RECT 77.735 7.495 77.905 7.665 ;
        RECT 78.105 7.495 78.275 7.665 ;
        RECT 78.475 7.495 78.645 7.665 ;
        RECT 78.845 7.495 79.015 7.665 ;
        RECT 79.215 7.495 79.385 7.665 ;
        RECT 79.585 7.495 79.755 7.665 ;
        RECT 79.955 7.495 80.125 7.665 ;
        RECT 80.325 7.495 80.495 7.665 ;
        RECT 80.695 7.495 80.865 7.665 ;
        RECT 81.065 7.495 81.235 7.665 ;
        RECT 81.435 7.495 81.605 7.665 ;
        RECT 81.805 7.495 81.975 7.665 ;
        RECT 82.545 7.495 82.715 7.665 ;
        RECT 82.915 7.495 83.085 7.665 ;
        RECT 83.285 7.495 83.455 7.665 ;
        RECT 83.655 7.495 83.825 7.665 ;
        RECT 84.025 7.495 84.195 7.665 ;
        RECT 84.395 7.495 84.565 7.665 ;
        RECT 84.765 7.495 84.935 7.665 ;
        RECT 85.135 7.495 85.305 7.665 ;
        RECT 85.505 7.495 85.675 7.665 ;
        RECT 85.875 7.495 86.045 7.665 ;
        RECT 86.245 7.495 86.415 7.665 ;
        RECT 86.615 7.495 86.785 7.665 ;
        RECT 87.355 7.495 87.525 7.665 ;
        RECT 87.725 7.495 87.895 7.665 ;
        RECT 88.095 7.495 88.265 7.665 ;
        RECT 88.465 7.495 88.635 7.665 ;
        RECT 88.835 7.495 89.005 7.665 ;
        RECT 89.205 7.495 89.375 7.665 ;
        RECT 89.575 7.495 89.745 7.665 ;
        RECT 89.945 7.495 90.115 7.665 ;
        RECT 90.685 7.495 90.855 7.665 ;
        RECT 91.055 7.495 91.225 7.665 ;
        RECT 91.425 7.495 91.595 7.665 ;
        RECT 91.795 7.495 91.965 7.665 ;
        RECT 92.165 7.495 92.335 7.665 ;
        RECT 92.535 7.495 92.705 7.665 ;
        RECT 92.905 7.495 93.075 7.665 ;
        RECT 93.275 7.495 93.445 7.665 ;
        RECT 94.015 7.495 94.185 7.665 ;
        RECT 94.385 7.495 94.555 7.665 ;
        RECT 94.755 7.495 94.925 7.665 ;
        RECT 95.125 7.495 95.295 7.665 ;
        RECT 95.495 7.495 95.665 7.665 ;
        RECT 95.865 7.495 96.035 7.665 ;
        RECT 96.235 7.495 96.405 7.665 ;
        RECT 96.605 7.495 96.775 7.665 ;
        RECT 97.345 7.495 97.515 7.665 ;
        RECT 97.715 7.495 97.885 7.665 ;
        RECT 98.085 7.495 98.255 7.665 ;
        RECT 98.455 7.495 98.625 7.665 ;
        RECT 98.825 7.495 98.995 7.665 ;
        RECT 1.515 4.165 1.685 4.335 ;
        RECT 2.625 2.315 2.795 2.485 ;
        RECT 3.735 3.425 3.905 3.595 ;
        RECT 4.475 2.685 4.645 2.855 ;
        RECT 6.325 2.685 6.495 2.855 ;
        RECT 8.545 3.795 8.715 3.965 ;
        RECT 9.285 3.425 9.455 3.595 ;
        RECT 11.135 2.685 11.305 2.855 ;
        RECT 12.245 3.055 12.415 3.225 ;
        RECT 13.355 3.795 13.525 3.965 ;
        RECT 14.095 2.685 14.265 2.855 ;
        RECT 15.945 2.685 16.115 2.855 ;
        RECT 18.905 3.795 19.075 3.965 ;
        RECT 20.755 3.425 20.925 3.595 ;
        RECT 22.975 3.425 23.145 3.595 ;
        RECT 23.715 2.685 23.885 2.855 ;
        RECT 25.565 2.685 25.735 2.855 ;
        RECT 27.785 3.795 27.955 3.965 ;
        RECT 28.525 4.905 28.695 5.075 ;
        RECT 28.525 3.425 28.695 3.595 ;
        RECT 32.595 3.425 32.765 3.595 ;
        RECT 33.335 2.685 33.505 2.855 ;
        RECT 35.185 2.685 35.355 2.855 ;
        RECT 37.405 3.795 37.575 3.965 ;
        RECT 38.145 3.425 38.315 3.595 ;
        RECT 39.995 2.685 40.165 2.855 ;
        RECT 42.215 3.795 42.385 3.965 ;
        RECT 42.955 2.685 43.125 2.855 ;
        RECT 44.805 2.685 44.975 2.855 ;
        RECT 45.915 4.535 46.085 4.705 ;
        RECT 47.765 3.795 47.935 3.965 ;
        RECT 49.615 3.425 49.785 3.595 ;
        RECT 51.835 3.425 52.005 3.595 ;
        RECT 52.575 2.685 52.745 2.855 ;
        RECT 54.425 2.685 54.595 2.855 ;
        RECT 56.645 3.795 56.815 3.965 ;
        RECT 57.385 3.795 57.555 3.965 ;
        RECT 57.385 3.425 57.555 3.595 ;
        RECT 61.455 3.425 61.625 3.595 ;
        RECT 62.195 2.685 62.365 2.855 ;
        RECT 64.045 2.685 64.215 2.855 ;
        RECT 66.265 3.795 66.435 3.965 ;
        RECT 67.005 3.425 67.175 3.595 ;
        RECT 68.855 2.685 69.025 2.855 ;
        RECT 71.075 3.795 71.245 3.965 ;
        RECT 71.815 2.685 71.985 2.855 ;
        RECT 73.665 2.685 73.835 2.855 ;
        RECT 76.625 3.795 76.795 3.965 ;
        RECT 78.475 3.425 78.645 3.595 ;
        RECT 80.695 2.315 80.865 2.485 ;
        RECT 81.435 2.685 81.605 2.855 ;
        RECT 83.285 2.685 83.455 2.855 ;
        RECT 84.395 3.055 84.565 3.225 ;
        RECT 85.505 3.795 85.675 3.965 ;
        RECT 89.095 5.305 89.265 5.475 ;
        RECT 87.725 4.535 87.895 4.705 ;
        RECT 86.245 2.315 86.415 2.485 ;
        RECT 88.835 4.165 89.005 4.335 ;
        RECT 91.095 5.305 91.265 5.475 ;
        RECT 92.415 5.305 92.585 5.475 ;
        RECT 91.425 4.535 91.595 4.705 ;
        RECT 89.135 1.275 89.305 1.445 ;
        RECT 94.435 5.305 94.605 5.475 ;
        RECT 92.905 2.175 93.075 2.345 ;
        RECT 92.465 1.275 92.635 1.445 ;
        RECT 94.385 2.175 94.555 2.345 ;
        RECT 95.495 4.165 95.665 4.335 ;
        RECT 96.235 4.165 96.405 4.335 ;
        RECT 97.715 4.165 97.885 4.335 ;
        RECT 95.795 1.275 95.965 1.445 ;
        RECT 98.455 4.165 98.625 4.335 ;
        RECT 0.775 0.095 0.945 0.265 ;
        RECT 1.145 0.095 1.315 0.265 ;
        RECT 1.515 0.095 1.685 0.265 ;
        RECT 1.885 0.095 2.055 0.265 ;
        RECT 2.255 0.095 2.425 0.265 ;
        RECT 2.625 0.095 2.795 0.265 ;
        RECT 2.995 0.095 3.165 0.265 ;
        RECT 3.365 0.095 3.535 0.265 ;
        RECT 3.735 0.095 3.905 0.265 ;
        RECT 4.105 0.095 4.275 0.265 ;
        RECT 4.475 0.095 4.645 0.265 ;
        RECT 4.845 0.095 5.015 0.265 ;
        RECT 5.585 0.095 5.755 0.265 ;
        RECT 5.955 0.095 6.125 0.265 ;
        RECT 6.325 0.095 6.495 0.265 ;
        RECT 6.695 0.095 6.865 0.265 ;
        RECT 7.065 0.095 7.235 0.265 ;
        RECT 7.435 0.095 7.605 0.265 ;
        RECT 7.805 0.095 7.975 0.265 ;
        RECT 8.175 0.095 8.345 0.265 ;
        RECT 8.545 0.095 8.715 0.265 ;
        RECT 8.915 0.095 9.085 0.265 ;
        RECT 9.285 0.095 9.455 0.265 ;
        RECT 9.655 0.095 9.825 0.265 ;
        RECT 10.395 0.095 10.565 0.265 ;
        RECT 10.765 0.095 10.935 0.265 ;
        RECT 11.135 0.095 11.305 0.265 ;
        RECT 11.505 0.095 11.675 0.265 ;
        RECT 11.875 0.095 12.045 0.265 ;
        RECT 12.245 0.095 12.415 0.265 ;
        RECT 12.615 0.095 12.785 0.265 ;
        RECT 12.985 0.095 13.155 0.265 ;
        RECT 13.355 0.095 13.525 0.265 ;
        RECT 13.725 0.095 13.895 0.265 ;
        RECT 14.095 0.095 14.265 0.265 ;
        RECT 14.465 0.095 14.635 0.265 ;
        RECT 15.205 0.095 15.375 0.265 ;
        RECT 15.575 0.095 15.745 0.265 ;
        RECT 15.945 0.095 16.115 0.265 ;
        RECT 16.315 0.095 16.485 0.265 ;
        RECT 16.685 0.095 16.855 0.265 ;
        RECT 17.055 0.095 17.225 0.265 ;
        RECT 17.425 0.095 17.595 0.265 ;
        RECT 17.795 0.095 17.965 0.265 ;
        RECT 18.165 0.095 18.335 0.265 ;
        RECT 18.535 0.095 18.705 0.265 ;
        RECT 18.905 0.095 19.075 0.265 ;
        RECT 19.275 0.095 19.445 0.265 ;
        RECT 20.015 0.095 20.185 0.265 ;
        RECT 20.385 0.095 20.555 0.265 ;
        RECT 20.755 0.095 20.925 0.265 ;
        RECT 21.125 0.095 21.295 0.265 ;
        RECT 21.495 0.095 21.665 0.265 ;
        RECT 21.865 0.095 22.035 0.265 ;
        RECT 22.235 0.095 22.405 0.265 ;
        RECT 22.605 0.095 22.775 0.265 ;
        RECT 22.975 0.095 23.145 0.265 ;
        RECT 23.345 0.095 23.515 0.265 ;
        RECT 23.715 0.095 23.885 0.265 ;
        RECT 24.085 0.095 24.255 0.265 ;
        RECT 24.825 0.095 24.995 0.265 ;
        RECT 25.195 0.095 25.365 0.265 ;
        RECT 25.565 0.095 25.735 0.265 ;
        RECT 25.935 0.095 26.105 0.265 ;
        RECT 26.305 0.095 26.475 0.265 ;
        RECT 26.675 0.095 26.845 0.265 ;
        RECT 27.045 0.095 27.215 0.265 ;
        RECT 27.415 0.095 27.585 0.265 ;
        RECT 27.785 0.095 27.955 0.265 ;
        RECT 28.155 0.095 28.325 0.265 ;
        RECT 28.525 0.095 28.695 0.265 ;
        RECT 28.895 0.095 29.065 0.265 ;
        RECT 29.635 0.095 29.805 0.265 ;
        RECT 30.005 0.095 30.175 0.265 ;
        RECT 30.375 0.095 30.545 0.265 ;
        RECT 30.745 0.095 30.915 0.265 ;
        RECT 31.115 0.095 31.285 0.265 ;
        RECT 31.485 0.095 31.655 0.265 ;
        RECT 31.855 0.095 32.025 0.265 ;
        RECT 32.225 0.095 32.395 0.265 ;
        RECT 32.595 0.095 32.765 0.265 ;
        RECT 32.965 0.095 33.135 0.265 ;
        RECT 33.335 0.095 33.505 0.265 ;
        RECT 33.705 0.095 33.875 0.265 ;
        RECT 34.445 0.095 34.615 0.265 ;
        RECT 34.815 0.095 34.985 0.265 ;
        RECT 35.185 0.095 35.355 0.265 ;
        RECT 35.555 0.095 35.725 0.265 ;
        RECT 35.925 0.095 36.095 0.265 ;
        RECT 36.295 0.095 36.465 0.265 ;
        RECT 36.665 0.095 36.835 0.265 ;
        RECT 37.035 0.095 37.205 0.265 ;
        RECT 37.405 0.095 37.575 0.265 ;
        RECT 37.775 0.095 37.945 0.265 ;
        RECT 38.145 0.095 38.315 0.265 ;
        RECT 38.515 0.095 38.685 0.265 ;
        RECT 39.255 0.095 39.425 0.265 ;
        RECT 39.625 0.095 39.795 0.265 ;
        RECT 39.995 0.095 40.165 0.265 ;
        RECT 40.365 0.095 40.535 0.265 ;
        RECT 40.735 0.095 40.905 0.265 ;
        RECT 41.105 0.095 41.275 0.265 ;
        RECT 41.475 0.095 41.645 0.265 ;
        RECT 41.845 0.095 42.015 0.265 ;
        RECT 42.215 0.095 42.385 0.265 ;
        RECT 42.585 0.095 42.755 0.265 ;
        RECT 42.955 0.095 43.125 0.265 ;
        RECT 43.325 0.095 43.495 0.265 ;
        RECT 44.065 0.095 44.235 0.265 ;
        RECT 44.435 0.095 44.605 0.265 ;
        RECT 44.805 0.095 44.975 0.265 ;
        RECT 45.175 0.095 45.345 0.265 ;
        RECT 45.545 0.095 45.715 0.265 ;
        RECT 45.915 0.095 46.085 0.265 ;
        RECT 46.285 0.095 46.455 0.265 ;
        RECT 46.655 0.095 46.825 0.265 ;
        RECT 47.025 0.095 47.195 0.265 ;
        RECT 47.395 0.095 47.565 0.265 ;
        RECT 47.765 0.095 47.935 0.265 ;
        RECT 48.135 0.095 48.305 0.265 ;
        RECT 48.875 0.095 49.045 0.265 ;
        RECT 49.245 0.095 49.415 0.265 ;
        RECT 49.615 0.095 49.785 0.265 ;
        RECT 49.985 0.095 50.155 0.265 ;
        RECT 50.355 0.095 50.525 0.265 ;
        RECT 50.725 0.095 50.895 0.265 ;
        RECT 51.095 0.095 51.265 0.265 ;
        RECT 51.465 0.095 51.635 0.265 ;
        RECT 51.835 0.095 52.005 0.265 ;
        RECT 52.205 0.095 52.375 0.265 ;
        RECT 52.575 0.095 52.745 0.265 ;
        RECT 52.945 0.095 53.115 0.265 ;
        RECT 53.685 0.095 53.855 0.265 ;
        RECT 54.055 0.095 54.225 0.265 ;
        RECT 54.425 0.095 54.595 0.265 ;
        RECT 54.795 0.095 54.965 0.265 ;
        RECT 55.165 0.095 55.335 0.265 ;
        RECT 55.535 0.095 55.705 0.265 ;
        RECT 55.905 0.095 56.075 0.265 ;
        RECT 56.275 0.095 56.445 0.265 ;
        RECT 56.645 0.095 56.815 0.265 ;
        RECT 57.015 0.095 57.185 0.265 ;
        RECT 57.385 0.095 57.555 0.265 ;
        RECT 57.755 0.095 57.925 0.265 ;
        RECT 58.495 0.095 58.665 0.265 ;
        RECT 58.865 0.095 59.035 0.265 ;
        RECT 59.235 0.095 59.405 0.265 ;
        RECT 59.605 0.095 59.775 0.265 ;
        RECT 59.975 0.095 60.145 0.265 ;
        RECT 60.345 0.095 60.515 0.265 ;
        RECT 60.715 0.095 60.885 0.265 ;
        RECT 61.085 0.095 61.255 0.265 ;
        RECT 61.455 0.095 61.625 0.265 ;
        RECT 61.825 0.095 61.995 0.265 ;
        RECT 62.195 0.095 62.365 0.265 ;
        RECT 62.565 0.095 62.735 0.265 ;
        RECT 63.305 0.095 63.475 0.265 ;
        RECT 63.675 0.095 63.845 0.265 ;
        RECT 64.045 0.095 64.215 0.265 ;
        RECT 64.415 0.095 64.585 0.265 ;
        RECT 64.785 0.095 64.955 0.265 ;
        RECT 65.155 0.095 65.325 0.265 ;
        RECT 65.525 0.095 65.695 0.265 ;
        RECT 65.895 0.095 66.065 0.265 ;
        RECT 66.265 0.095 66.435 0.265 ;
        RECT 66.635 0.095 66.805 0.265 ;
        RECT 67.005 0.095 67.175 0.265 ;
        RECT 67.375 0.095 67.545 0.265 ;
        RECT 68.115 0.095 68.285 0.265 ;
        RECT 68.485 0.095 68.655 0.265 ;
        RECT 68.855 0.095 69.025 0.265 ;
        RECT 69.225 0.095 69.395 0.265 ;
        RECT 69.595 0.095 69.765 0.265 ;
        RECT 69.965 0.095 70.135 0.265 ;
        RECT 70.335 0.095 70.505 0.265 ;
        RECT 70.705 0.095 70.875 0.265 ;
        RECT 71.075 0.095 71.245 0.265 ;
        RECT 71.445 0.095 71.615 0.265 ;
        RECT 71.815 0.095 71.985 0.265 ;
        RECT 72.185 0.095 72.355 0.265 ;
        RECT 72.925 0.095 73.095 0.265 ;
        RECT 73.295 0.095 73.465 0.265 ;
        RECT 73.665 0.095 73.835 0.265 ;
        RECT 74.035 0.095 74.205 0.265 ;
        RECT 74.405 0.095 74.575 0.265 ;
        RECT 74.775 0.095 74.945 0.265 ;
        RECT 75.145 0.095 75.315 0.265 ;
        RECT 75.515 0.095 75.685 0.265 ;
        RECT 75.885 0.095 76.055 0.265 ;
        RECT 76.255 0.095 76.425 0.265 ;
        RECT 76.625 0.095 76.795 0.265 ;
        RECT 76.995 0.095 77.165 0.265 ;
        RECT 77.735 0.095 77.905 0.265 ;
        RECT 78.105 0.095 78.275 0.265 ;
        RECT 78.475 0.095 78.645 0.265 ;
        RECT 78.845 0.095 79.015 0.265 ;
        RECT 79.215 0.095 79.385 0.265 ;
        RECT 79.585 0.095 79.755 0.265 ;
        RECT 79.955 0.095 80.125 0.265 ;
        RECT 80.325 0.095 80.495 0.265 ;
        RECT 80.695 0.095 80.865 0.265 ;
        RECT 81.065 0.095 81.235 0.265 ;
        RECT 81.435 0.095 81.605 0.265 ;
        RECT 81.805 0.095 81.975 0.265 ;
        RECT 82.545 0.095 82.715 0.265 ;
        RECT 82.915 0.095 83.085 0.265 ;
        RECT 83.285 0.095 83.455 0.265 ;
        RECT 83.655 0.095 83.825 0.265 ;
        RECT 84.025 0.095 84.195 0.265 ;
        RECT 84.395 0.095 84.565 0.265 ;
        RECT 84.765 0.095 84.935 0.265 ;
        RECT 85.135 0.095 85.305 0.265 ;
        RECT 85.505 0.095 85.675 0.265 ;
        RECT 85.875 0.095 86.045 0.265 ;
        RECT 86.245 0.095 86.415 0.265 ;
        RECT 86.615 0.095 86.785 0.265 ;
        RECT 87.355 0.095 87.525 0.265 ;
        RECT 87.725 0.095 87.895 0.265 ;
        RECT 88.095 0.095 88.265 0.265 ;
        RECT 88.465 0.095 88.635 0.265 ;
        RECT 88.835 0.095 89.005 0.265 ;
        RECT 89.205 0.095 89.375 0.265 ;
        RECT 89.575 0.095 89.745 0.265 ;
        RECT 89.945 0.095 90.115 0.265 ;
        RECT 90.685 0.095 90.855 0.265 ;
        RECT 91.055 0.095 91.225 0.265 ;
        RECT 91.425 0.095 91.595 0.265 ;
        RECT 91.795 0.095 91.965 0.265 ;
        RECT 92.165 0.095 92.335 0.265 ;
        RECT 92.535 0.095 92.705 0.265 ;
        RECT 92.905 0.095 93.075 0.265 ;
        RECT 93.275 0.095 93.445 0.265 ;
        RECT 94.015 0.095 94.185 0.265 ;
        RECT 94.385 0.095 94.555 0.265 ;
        RECT 94.755 0.095 94.925 0.265 ;
        RECT 95.125 0.095 95.295 0.265 ;
        RECT 95.495 0.095 95.665 0.265 ;
        RECT 95.865 0.095 96.035 0.265 ;
        RECT 96.235 0.095 96.405 0.265 ;
        RECT 96.605 0.095 96.775 0.265 ;
        RECT 97.345 0.095 97.515 0.265 ;
        RECT 97.715 0.095 97.885 0.265 ;
        RECT 98.085 0.095 98.255 0.265 ;
        RECT 98.455 0.095 98.625 0.265 ;
        RECT 98.825 0.095 98.995 0.265 ;
      LAYER met1 ;
        RECT 89.065 5.475 89.295 5.505 ;
        RECT 91.065 5.475 91.295 5.505 ;
        RECT 92.385 5.475 92.615 5.505 ;
        RECT 94.405 5.475 94.635 5.505 ;
        RECT 89.035 5.305 91.325 5.475 ;
        RECT 92.355 5.305 94.665 5.475 ;
        RECT 89.065 5.275 89.295 5.305 ;
        RECT 91.065 5.275 91.295 5.305 ;
        RECT 92.385 5.275 92.615 5.305 ;
        RECT 94.405 5.275 94.635 5.305 ;
        RECT 28.495 5.075 28.725 5.105 ;
        RECT 28.465 4.905 75.685 5.075 ;
        RECT 28.495 4.875 28.725 4.905 ;
        RECT 75.515 4.705 75.685 4.905 ;
        RECT 87.695 4.705 87.925 4.735 ;
        RECT 91.395 4.705 91.625 4.735 ;
        RECT 75.515 4.545 91.655 4.705 ;
        RECT 75.595 4.535 91.655 4.545 ;
        RECT 87.695 4.505 87.925 4.535 ;
        RECT 91.395 4.505 91.625 4.535 ;
        RECT 88.805 4.335 89.035 4.365 ;
        RECT 95.465 4.335 95.695 4.365 ;
        RECT 96.205 4.335 96.435 4.365 ;
        RECT 97.685 4.335 97.915 4.365 ;
        RECT 65.525 4.165 95.725 4.335 ;
        RECT 96.175 4.165 97.945 4.335 ;
        RECT 8.515 3.965 8.745 3.995 ;
        RECT 13.325 3.965 13.555 3.995 ;
        RECT 18.875 3.965 19.105 3.995 ;
        RECT 27.755 3.965 27.985 3.995 ;
        RECT 37.375 3.965 37.605 3.995 ;
        RECT 42.185 3.965 42.415 3.995 ;
        RECT 47.735 3.965 47.965 3.995 ;
        RECT 56.615 3.965 56.845 3.995 ;
        RECT 57.355 3.965 57.585 3.995 ;
        RECT 65.525 3.965 65.695 4.165 ;
        RECT 88.805 4.135 89.035 4.165 ;
        RECT 95.465 4.135 95.695 4.165 ;
        RECT 96.205 4.135 96.435 4.165 ;
        RECT 97.685 4.135 97.915 4.165 ;
        RECT 66.235 3.965 66.465 3.995 ;
        RECT 71.045 3.965 71.275 3.995 ;
        RECT 76.595 3.965 76.825 3.995 ;
        RECT 85.475 3.965 85.705 3.995 ;
        RECT 8.485 3.795 28.015 3.965 ;
        RECT 37.345 3.795 56.875 3.965 ;
        RECT 57.325 3.795 65.695 3.965 ;
        RECT 66.205 3.795 85.735 3.965 ;
        RECT 8.515 3.765 8.745 3.795 ;
        RECT 13.325 3.765 13.555 3.795 ;
        RECT 18.875 3.765 19.105 3.795 ;
        RECT 27.755 3.765 27.985 3.795 ;
        RECT 37.375 3.765 37.605 3.795 ;
        RECT 42.185 3.765 42.415 3.795 ;
        RECT 47.735 3.765 47.965 3.795 ;
        RECT 56.615 3.765 56.845 3.795 ;
        RECT 57.355 3.765 57.585 3.795 ;
        RECT 66.235 3.765 66.465 3.795 ;
        RECT 71.045 3.765 71.275 3.795 ;
        RECT 76.595 3.765 76.825 3.795 ;
        RECT 85.475 3.765 85.705 3.795 ;
        RECT 3.705 3.595 3.935 3.625 ;
        RECT 9.255 3.595 9.485 3.625 ;
        RECT 20.725 3.595 20.955 3.625 ;
        RECT 22.945 3.595 23.175 3.625 ;
        RECT 28.495 3.595 28.725 3.625 ;
        RECT 32.565 3.595 32.795 3.625 ;
        RECT 38.115 3.595 38.345 3.625 ;
        RECT 49.585 3.595 49.815 3.625 ;
        RECT 51.805 3.595 52.035 3.625 ;
        RECT 57.355 3.595 57.585 3.625 ;
        RECT 61.425 3.595 61.655 3.625 ;
        RECT 66.975 3.595 67.205 3.625 ;
        RECT 78.445 3.595 78.675 3.625 ;
        RECT 3.675 3.425 20.985 3.595 ;
        RECT 22.915 3.425 28.755 3.595 ;
        RECT 32.535 3.425 49.845 3.595 ;
        RECT 51.775 3.425 57.615 3.595 ;
        RECT 61.395 3.425 78.705 3.595 ;
        RECT 3.705 3.395 3.935 3.425 ;
        RECT 9.255 3.395 9.485 3.425 ;
        RECT 20.725 3.395 20.955 3.425 ;
        RECT 22.945 3.395 23.175 3.425 ;
        RECT 28.495 3.395 28.725 3.425 ;
        RECT 32.565 3.395 32.795 3.425 ;
        RECT 38.115 3.395 38.345 3.425 ;
        RECT 49.585 3.395 49.815 3.425 ;
        RECT 51.805 3.395 52.035 3.425 ;
        RECT 57.355 3.395 57.585 3.425 ;
        RECT 61.425 3.395 61.655 3.425 ;
        RECT 66.975 3.395 67.205 3.425 ;
        RECT 78.445 3.395 78.675 3.425 ;
        RECT 4.445 2.855 4.675 2.885 ;
        RECT 6.295 2.855 6.525 2.885 ;
        RECT 11.105 2.855 11.335 2.885 ;
        RECT 14.065 2.855 14.295 2.885 ;
        RECT 15.915 2.855 16.145 2.885 ;
        RECT 23.685 2.855 23.915 2.885 ;
        RECT 25.535 2.855 25.765 2.885 ;
        RECT 33.305 2.855 33.535 2.885 ;
        RECT 35.155 2.855 35.385 2.885 ;
        RECT 39.965 2.855 40.195 2.885 ;
        RECT 42.925 2.855 43.155 2.885 ;
        RECT 44.775 2.855 45.005 2.885 ;
        RECT 52.545 2.855 52.775 2.885 ;
        RECT 54.395 2.855 54.625 2.885 ;
        RECT 62.165 2.855 62.395 2.885 ;
        RECT 64.015 2.855 64.245 2.885 ;
        RECT 68.825 2.855 69.055 2.885 ;
        RECT 71.785 2.855 72.015 2.885 ;
        RECT 73.635 2.855 73.865 2.885 ;
        RECT 81.405 2.855 81.635 2.885 ;
        RECT 83.255 2.855 83.485 2.885 ;
        RECT 4.415 2.685 11.365 2.855 ;
        RECT 14.035 2.685 16.175 2.855 ;
        RECT 23.655 2.685 25.795 2.855 ;
        RECT 33.275 2.685 40.225 2.855 ;
        RECT 42.895 2.685 45.035 2.855 ;
        RECT 52.515 2.685 54.655 2.855 ;
        RECT 62.135 2.685 69.085 2.855 ;
        RECT 71.755 2.685 73.895 2.855 ;
        RECT 81.375 2.685 83.515 2.855 ;
        RECT 4.445 2.655 4.675 2.685 ;
        RECT 6.295 2.655 6.525 2.685 ;
        RECT 11.105 2.655 11.335 2.685 ;
        RECT 14.065 2.655 14.295 2.685 ;
        RECT 15.915 2.655 16.145 2.685 ;
        RECT 23.685 2.655 23.915 2.685 ;
        RECT 25.535 2.655 25.765 2.685 ;
        RECT 33.305 2.655 33.535 2.685 ;
        RECT 35.155 2.655 35.385 2.685 ;
        RECT 39.965 2.655 40.195 2.685 ;
        RECT 42.925 2.655 43.155 2.685 ;
        RECT 44.775 2.655 45.005 2.685 ;
        RECT 52.545 2.655 52.775 2.685 ;
        RECT 54.395 2.655 54.625 2.685 ;
        RECT 62.165 2.655 62.395 2.685 ;
        RECT 64.015 2.655 64.245 2.685 ;
        RECT 68.825 2.655 69.055 2.685 ;
        RECT 71.785 2.655 72.015 2.685 ;
        RECT 73.635 2.655 73.865 2.685 ;
        RECT 81.405 2.655 81.635 2.685 ;
        RECT 83.255 2.655 83.485 2.685 ;
        RECT 80.665 2.485 80.895 2.515 ;
        RECT 86.215 2.485 86.445 2.515 ;
        RECT 80.635 2.345 93.105 2.485 ;
        RECT 94.355 2.345 94.585 2.375 ;
        RECT 80.635 2.315 94.615 2.345 ;
        RECT 80.665 2.285 80.895 2.315 ;
        RECT 86.215 2.285 86.445 2.315 ;
        RECT 92.845 2.175 94.615 2.315 ;
        RECT 92.875 2.145 93.105 2.175 ;
        RECT 94.355 2.145 94.585 2.175 ;
        RECT 89.105 1.445 89.335 1.475 ;
        RECT 92.435 1.445 92.665 1.475 ;
        RECT 95.765 1.445 95.995 1.475 ;
        RECT 89.075 1.275 96.025 1.445 ;
        RECT 89.105 1.245 89.335 1.275 ;
        RECT 92.435 1.245 92.665 1.275 ;
        RECT 95.765 1.245 95.995 1.275 ;
  END
END TMRDFFSNRNQX1
END LIBRARY

